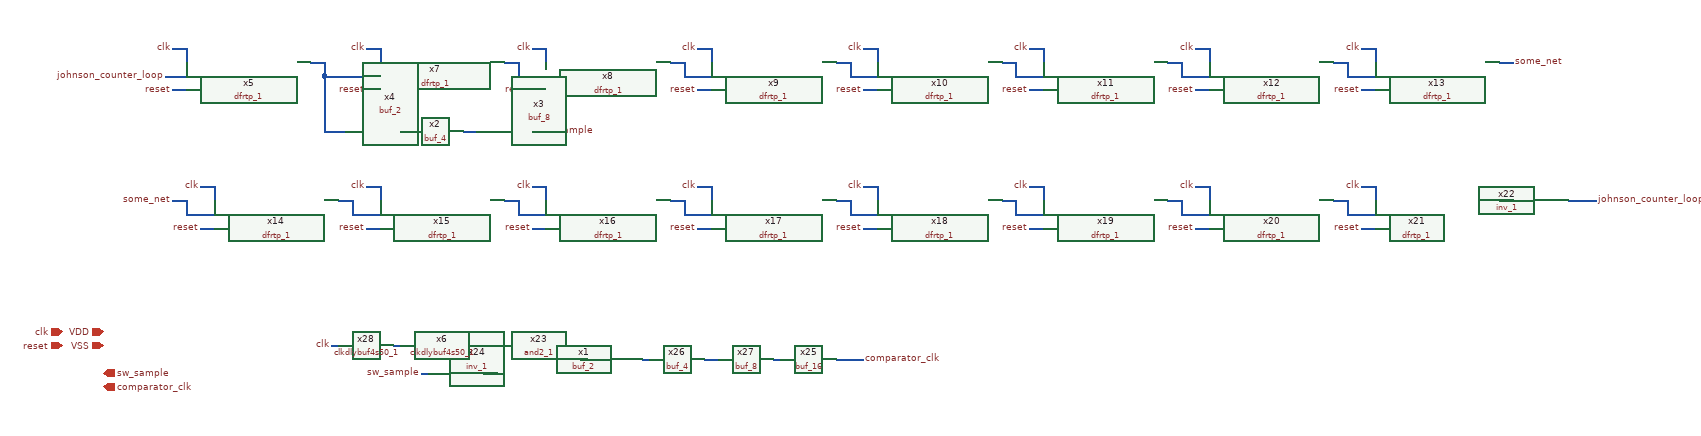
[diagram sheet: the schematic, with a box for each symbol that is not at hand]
v {xschem version=3.1.0 file_version=1.2
}
G {}
K {}
V {}
S {}
E {}
N 220 -540 240 -540 {
lab=clk}
N 240 -540 240 -520 {
lab=clk}
N 220 -480 240 -480 {
lab=reset}
N 500 -540 520 -540 {
lab=clk}
N 520 -540 520 -520 {
lab=clk}
N 420 -520 440 -520 {
lab=#net1}
N 440 -520 440 -500 {
lab=#net1}
N 440 -500 520 -500 {
lab=#net1}
N 500 -480 520 -480 {
lab=reset}
N 700 -520 720 -520 {
lab=#net2}
N 720 -520 720 -500 {
lab=#net2}
N 720 -500 760 -500 {
lab=#net2}
N 740 -540 760 -540 {
lab=clk}
N 760 -540 760 -520 {
lab=clk}
N 740 -480 760 -480 {
lab=reset}
N 980 -540 1000 -540 {
lab=clk}
N 1000 -540 1000 -520 {
lab=clk}
N 940 -520 960 -520 {
lab=#net3}
N 960 -520 960 -500 {
lab=#net3}
N 960 -500 1000 -500 {
lab=#net3}
N 980 -480 1000 -480 {
lab=reset}
N 1180 -520 1200 -520 {
lab=#net4}
N 1200 -520 1200 -500 {
lab=#net4}
N 1200 -500 1240 -500 {
lab=#net4}
N 1220 -540 1240 -540 {
lab=clk}
N 1240 -540 1240 -520 {
lab=clk}
N 1220 -480 1240 -480 {
lab=reset}
N 1460 -540 1480 -540 {
lab=clk}
N 1480 -540 1480 -520 {
lab=clk}
N 1420 -520 1440 -520 {
lab=#net5}
N 1440 -520 1440 -500 {
lab=#net5}
N 1440 -500 1480 -500 {
lab=#net5}
N 1460 -480 1480 -480 {
lab=reset}
N 1660 -520 1680 -520 {
lab=#net6}
N 1680 -520 1680 -500 {
lab=#net6}
N 1680 -500 1720 -500 {
lab=#net6}
N 1700 -540 1720 -540 {
lab=clk}
N 1720 -540 1720 -520 {
lab=clk}
N 1700 -480 1720 -480 {
lab=reset}
N 1940 -540 1960 -540 {
lab=clk}
N 1960 -540 1960 -520 {
lab=clk}
N 1900 -520 1920 -520 {
lab=#net7}
N 1920 -520 1920 -500 {
lab=#net7}
N 1920 -500 1960 -500 {
lab=#net7}
N 1940 -480 1960 -480 {
lab=reset}
N 220 -320 240 -320 {
lab=#net8}
N 240 -320 240 -300 {
lab=#net8}
N 240 -300 280 -300 {
lab=#net8}
N 260 -340 280 -340 {
lab=clk}
N 280 -340 280 -320 {
lab=clk}
N 260 -280 280 -280 {
lab=reset}
N 500 -340 520 -340 {
lab=clk}
N 520 -340 520 -320 {
lab=clk}
N 460 -320 480 -320 {
lab=#net9}
N 480 -320 480 -300 {
lab=#net9}
N 480 -300 520 -300 {
lab=#net9}
N 500 -280 520 -280 {
lab=reset}
N 700 -320 720 -320 {
lab=#net10}
N 720 -320 720 -300 {
lab=#net10}
N 720 -300 760 -300 {
lab=#net10}
N 740 -340 760 -340 {
lab=clk}
N 760 -340 760 -320 {
lab=clk}
N 740 -280 760 -280 {
lab=reset}
N 980 -340 1000 -340 {
lab=clk}
N 1000 -340 1000 -320 {
lab=clk}
N 940 -320 960 -320 {
lab=#net11}
N 960 -320 960 -300 {
lab=#net11}
N 960 -300 1000 -300 {
lab=#net11}
N 980 -280 1000 -280 {
lab=reset}
N 1180 -320 1200 -320 {
lab=#net12}
N 1200 -320 1200 -300 {
lab=#net12}
N 1200 -300 1240 -300 {
lab=#net12}
N 1220 -340 1240 -340 {
lab=clk}
N 1240 -340 1240 -320 {
lab=clk}
N 1220 -280 1240 -280 {
lab=reset}
N 1460 -340 1480 -340 {
lab=clk}
N 1480 -340 1480 -320 {
lab=clk}
N 1420 -320 1440 -320 {
lab=#net13}
N 1440 -320 1440 -300 {
lab=#net13}
N 1440 -300 1480 -300 {
lab=#net13}
N 1460 -280 1480 -280 {
lab=reset}
N 1660 -320 1680 -320 {
lab=#net14}
N 1680 -320 1680 -300 {
lab=#net14}
N 1680 -300 1720 -300 {
lab=#net14}
N 1700 -340 1720 -340 {
lab=clk}
N 1720 -340 1720 -320 {
lab=clk}
N 1700 -280 1720 -280 {
lab=reset}
N 1940 -340 1960 -340 {
lab=clk}
N 1960 -340 1960 -320 {
lab=clk}
N 1900 -320 1920 -320 {
lab=#net15}
N 1920 -320 1920 -300 {
lab=#net15}
N 1920 -300 1960 -300 {
lab=#net15}
N 1940 -280 1960 -280 {
lab=reset}
N 210 -500 240 -500 {
lab=johnson_counter_loop}
N 2240 -320 2280 -320 {
lab=johnson_counter_loop}
N 2140 -320 2160 -320 {
lab=#net16}
N 440 -500 440 -440 {
lab=#net1}
N 670 -70 690 -70 {
lab=#net17}
N 670 -110 690 -110 {
lab=#net18}
N 580 -70 590 -70 {
lab=sw_sample}
N 990 -90 1010 -90 {
lab=#net19}
N 1090 -90 1100 -90 {
lab=#net20}
N 1180 -90 1220 -90 {
lab=comparator_clk}
N 810 -90 820 -90 {
lab=#net21}
N 900 -90 910 -90 {
lab=#net22}
N 640 -420 660 -420 {
lab=#net23}
N 740 -420 750 -420 {
lab=sw_sample}
N 460 -420 470 -420 {
lab=#net1}
N 550 -420 560 -420 {
lab=#net24}
N 440 -440 440 -420 {
lab=#net1}
N 440 -420 460 -420 {
lab=#net1}
N 630 -110 670 -110 {
lab=#net18}
N 540 -110 550 -110 {
lab=#net25}
N 450 -110 460 -110 {
lab=clk}
N 2140 -520 2160 -520 {
lab=some_net}
C {devices/title.sym} 160 30 0 0 {name=l1 author="Dr. Aubrey Beal, Dr. Phillip Bailey, Micah Tseng"
}
C {devices/lab_pin.sym} 750 -420 2 0 {name=l217 sig_type=std_logic lab=sw_sample
}
C {sky130_stdcells/dfrtp_1.sym} 330 -500 0 0 {name=x5 VGND=VSS VNB=VSS VPB=VDD VPWR=VDD prefix=sky130_fd_sc_hd__ 
}
C {sky130_stdcells/dfrtp_1.sym} 610 -500 0 0 {name=x7 VGND=VSS VNB=VSS VPB=VDD VPWR=VDD prefix=sky130_fd_sc_hd__ 
}
C {devices/lab_pin.sym} 220 -540 0 0 {name=l20 sig_type=std_logic lab=clk
}
C {devices/lab_pin.sym} 220 -480 0 0 {name=l22 sig_type=std_logic lab=reset
}
C {devices/lab_pin.sym} 500 -540 0 0 {name=l23 sig_type=std_logic lab=clk
}
C {devices/lab_pin.sym} 500 -480 0 0 {name=l24 sig_type=std_logic lab=reset
}
C {sky130_stdcells/dfrtp_1.sym} 850 -500 0 0 {name=x8 VGND=VSS VNB=VSS VPB=VDD VPWR=VDD prefix=sky130_fd_sc_hd__ 
}
C {sky130_stdcells/dfrtp_1.sym} 1090 -500 0 0 {name=x9 VGND=VSS VNB=VSS VPB=VDD VPWR=VDD prefix=sky130_fd_sc_hd__ 
}
C {devices/lab_pin.sym} 740 -540 0 0 {name=l27 sig_type=std_logic lab=clk
}
C {devices/lab_pin.sym} 740 -480 0 0 {name=l28 sig_type=std_logic lab=reset
}
C {devices/lab_pin.sym} 980 -540 0 0 {name=l32 sig_type=std_logic lab=clk
}
C {devices/lab_pin.sym} 980 -480 0 0 {name=l33 sig_type=std_logic lab=reset
}
C {sky130_stdcells/dfrtp_1.sym} 1330 -500 0 0 {name=x10 VGND=VSS VNB=VSS VPB=VDD VPWR=VDD prefix=sky130_fd_sc_hd__ 
}
C {sky130_stdcells/dfrtp_1.sym} 1570 -500 0 0 {name=x11 VGND=VSS VNB=VSS VPB=VDD VPWR=VDD prefix=sky130_fd_sc_hd__ 
}
C {devices/lab_pin.sym} 1220 -540 0 0 {name=l34 sig_type=std_logic lab=clk
}
C {devices/lab_pin.sym} 1220 -480 0 0 {name=l35 sig_type=std_logic lab=reset
}
C {devices/lab_pin.sym} 1460 -540 0 0 {name=l36 sig_type=std_logic lab=clk
}
C {devices/lab_pin.sym} 1460 -480 0 0 {name=l37 sig_type=std_logic lab=reset
}
C {sky130_stdcells/dfrtp_1.sym} 1810 -500 0 0 {name=x12 VGND=VSS VNB=VSS VPB=VDD VPWR=VDD prefix=sky130_fd_sc_hd__ 
}
C {sky130_stdcells/dfrtp_1.sym} 2050 -500 0 0 {name=x13 VGND=VSS VNB=VSS VPB=VDD VPWR=VDD prefix=sky130_fd_sc_hd__ 
}
C {devices/lab_pin.sym} 1700 -540 0 0 {name=l38 sig_type=std_logic lab=clk
}
C {devices/lab_pin.sym} 1700 -480 0 0 {name=l39 sig_type=std_logic lab=reset
}
C {devices/lab_pin.sym} 1940 -540 0 0 {name=l40 sig_type=std_logic lab=clk
}
C {devices/lab_pin.sym} 1940 -480 0 0 {name=l41 sig_type=std_logic lab=reset
}
C {sky130_stdcells/dfrtp_1.sym} 370 -300 0 0 {name=x14 VGND=VSS VNB=VSS VPB=VDD VPWR=VDD prefix=sky130_fd_sc_hd__ 
}
C {sky130_stdcells/dfrtp_1.sym} 610 -300 0 0 {name=x15 VGND=VSS VNB=VSS VPB=VDD VPWR=VDD prefix=sky130_fd_sc_hd__ 
}
C {devices/lab_pin.sym} 260 -340 0 0 {name=l42 sig_type=std_logic lab=clk
}
C {devices/lab_pin.sym} 260 -280 0 0 {name=l43 sig_type=std_logic lab=reset
}
C {devices/lab_pin.sym} 500 -340 0 0 {name=l44 sig_type=std_logic lab=clk
}
C {devices/lab_pin.sym} 500 -280 0 0 {name=l46 sig_type=std_logic lab=reset
}
C {sky130_stdcells/dfrtp_1.sym} 850 -300 0 0 {name=x16 VGND=VSS VNB=VSS VPB=VDD VPWR=VDD prefix=sky130_fd_sc_hd__ 
}
C {sky130_stdcells/dfrtp_1.sym} 1090 -300 0 0 {name=x17 VGND=VSS VNB=VSS VPB=VDD VPWR=VDD prefix=sky130_fd_sc_hd__ 
}
C {devices/lab_pin.sym} 740 -340 0 0 {name=l47 sig_type=std_logic lab=clk
}
C {devices/lab_pin.sym} 740 -280 0 0 {name=l48 sig_type=std_logic lab=reset
}
C {devices/lab_pin.sym} 980 -340 0 0 {name=l49 sig_type=std_logic lab=clk
}
C {devices/lab_pin.sym} 980 -280 0 0 {name=l50 sig_type=std_logic lab=reset
}
C {sky130_stdcells/dfrtp_1.sym} 1330 -300 0 0 {name=x18 VGND=VSS VNB=VSS VPB=VDD VPWR=VDD prefix=sky130_fd_sc_hd__ 
}
C {sky130_stdcells/dfrtp_1.sym} 1570 -300 0 0 {name=x19 VGND=VSS VNB=VSS VPB=VDD VPWR=VDD prefix=sky130_fd_sc_hd__ 
}
C {devices/lab_pin.sym} 1220 -340 0 0 {name=l51 sig_type=std_logic lab=clk
}
C {devices/lab_pin.sym} 1220 -280 0 0 {name=l52 sig_type=std_logic lab=reset
}
C {devices/lab_pin.sym} 1460 -340 0 0 {name=l53 sig_type=std_logic lab=clk
}
C {devices/lab_pin.sym} 1460 -280 0 0 {name=l54 sig_type=std_logic lab=reset
}
C {sky130_stdcells/dfrtp_1.sym} 1810 -300 0 0 {name=x20 VGND=VSS VNB=VSS VPB=VDD VPWR=VDD prefix=sky130_fd_sc_hd__ 
}
C {devices/lab_pin.sym} 1700 -340 0 0 {name=l55 sig_type=std_logic lab=clk
}
C {devices/lab_pin.sym} 1700 -280 0 0 {name=l56 sig_type=std_logic lab=reset
}
C {devices/lab_pin.sym} 1940 -340 0 0 {name=l57 sig_type=std_logic lab=clk
}
C {devices/lab_pin.sym} 1940 -280 0 0 {name=l58 sig_type=std_logic lab=reset
}
C {devices/lab_pin.sym} 210 -500 0 0 {name=l59 sig_type=std_logic lab=johnson_counter_loop

}
C {devices/lab_pin.sym} 2280 -320 2 0 {name=l60 sig_type=std_logic lab=johnson_counter_loop

}
C {sky130_stdcells/dfrtp_1.sym} 2050 -300 0 0 {name=x21 VGND=VSS VNB=VSS VPB=VDD VPWR=VDD prefix=sky130_fd_sc_hd__ 
}
C {sky130_stdcells/inv_1.sym} 2200 -320 0 0 {name=x22 VGND=VSS VNB=VSS VPB=VDD VPWR=VDD prefix=sky130_fd_sc_hd__ 
}
C {devices/lab_pin.sym} 450 -110 0 0 {name=l31 sig_type=std_logic lab=clk
}
C {sky130_stdcells/and2_1.sym} 750 -90 0 0 {name=x23 VGND=VSS VNB=VSS VPB=VDD VPWR=VDD prefix=sky130_fd_sc_hd__ 
}
C {sky130_stdcells/inv_1.sym} 630 -70 0 0 {name=x24 VGND=VSS VNB=VSS VPB=VDD VPWR=VDD prefix=sky130_fd_sc_hd__ 
}
C {devices/lab_pin.sym} 580 -70 0 0 {name=l61 sig_type=std_logic lab=sw_sample
}
C {devices/lab_pin.sym} 1220 -90 2 0 {name=l62 sig_type=std_logic lab=comparator_clk
}
C {devices/iopin.sym} 120 -130 0 0 {name=p1 lab=VDD
}
C {devices/ipin.sym} 60 -130 0 0 {name=p2 lab=clk
}
C {devices/opin.sym} 120 -70 0 0 {name=p3 lab=sw_sample
}
C {devices/iopin.sym} 120 -110 0 0 {name=p4 lab=VSS
}
C {devices/opin.sym} 120 -50 0 0 {name=p5 lab=comparator_clk
}
C {devices/ipin.sym} 60 -110 0 0 {name=p6 lab=reset
}
C {sky130_stdcells/buf_16.sym} 1140 -90 0 0 {name=x25 VGND=VSS VNB=VSS VPB=VDD VPWR=VDD prefix=sky130_fd_sc_hd__ 
}
C {sky130_stdcells/buf_4.sym} 950 -90 0 0 {name=x26 VGND=VSS VNB=VSS VPB=VDD VPWR=VDD prefix=sky130_fd_sc_hd__ 
}
C {sky130_stdcells/buf_8.sym} 1050 -90 0 0 {name=x27 VGND=VSS VNB=VSS VPB=VDD VPWR=VDD prefix=sky130_fd_sc_hd__ 
}
C {sky130_stdcells/buf_2.sym} 860 -90 0 0 {name=x1 VGND=VSS VNB=VSS VPB=VDD VPWR=VDD prefix=sky130_fd_sc_hd__ 
}
C {sky130_stdcells/buf_4.sym} 600 -420 0 0 {name=x2 VGND=VSS VNB=VSS VPB=VDD VPWR=VDD prefix=sky130_fd_sc_hd__ 
}
C {sky130_stdcells/buf_8.sym} 700 -420 0 0 {name=x3 VGND=VSS VNB=VSS VPB=VDD VPWR=VDD prefix=sky130_fd_sc_hd__ 
}
C {sky130_stdcells/buf_2.sym} 510 -420 0 0 {name=x4 VGND=VSS VNB=VSS VPB=VDD VPWR=VDD prefix=sky130_fd_sc_hd__ 
}
C {sky130_stdcells/clkdlybuf4s50_1.sym} 590 -110 0 0 {name=x6 VGND=VSS VNB=VSS VPB=VDD VPWR=VDD prefix=sky130_fd_sc_hd__ 
}
C {sky130_stdcells/clkdlybuf4s50_1.sym} 500 -110 0 0 {name=x28 VGND=VSS VNB=VSS VPB=VDD VPWR=VDD prefix=sky130_fd_sc_hd__ 
}
C {devices/lab_pin.sym} 2160 -520 2 0 {name=l1 sig_type=std_logic lab=some_net
}
C {devices/lab_pin.sym} 220 -320 0 0 {name=l1 sig_type=std_logic lab=some_net
}
